VERSION 5.8 ;
DIVIDERCHAR "/" ;
BUSBITCHARS "[]" ;

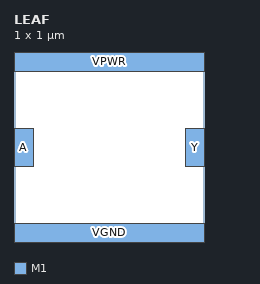
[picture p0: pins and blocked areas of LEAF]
MACRO LEAF
  CLASS CORE ;
  ORIGIN 0.000 0.000 ;
  SIZE 1.000 BY 1.000 ;
  SYMMETRY X Y R90 ;
  PIN A
    DIRECTION INPUT ;
    USE SIGNAL ;
    PORT
      LAYER M1 ;
        RECT 0.000 0.400 0.100 0.600 ;
    END
  END A
  PIN Y
    DIRECTION OUTPUT ;
    USE SIGNAL ;
    PORT
      LAYER M1 ;
        RECT 0.900 0.400 1.000 0.600 ;
    END
  END Y
  PIN VPWR
    DIRECTION INOUT ;
    USE POWER ;
    PORT
      LAYER M1 ;
        RECT 0.000 0.900 1.000 1.000 ;
    END
  END VPWR
  PIN VGND
    DIRECTION INOUT ;
    USE GROUND ;
    PORT
      LAYER M1 ;
        RECT 0.000 0.000 1.000 0.100 ;
    END
  END VGND
END LEAF
